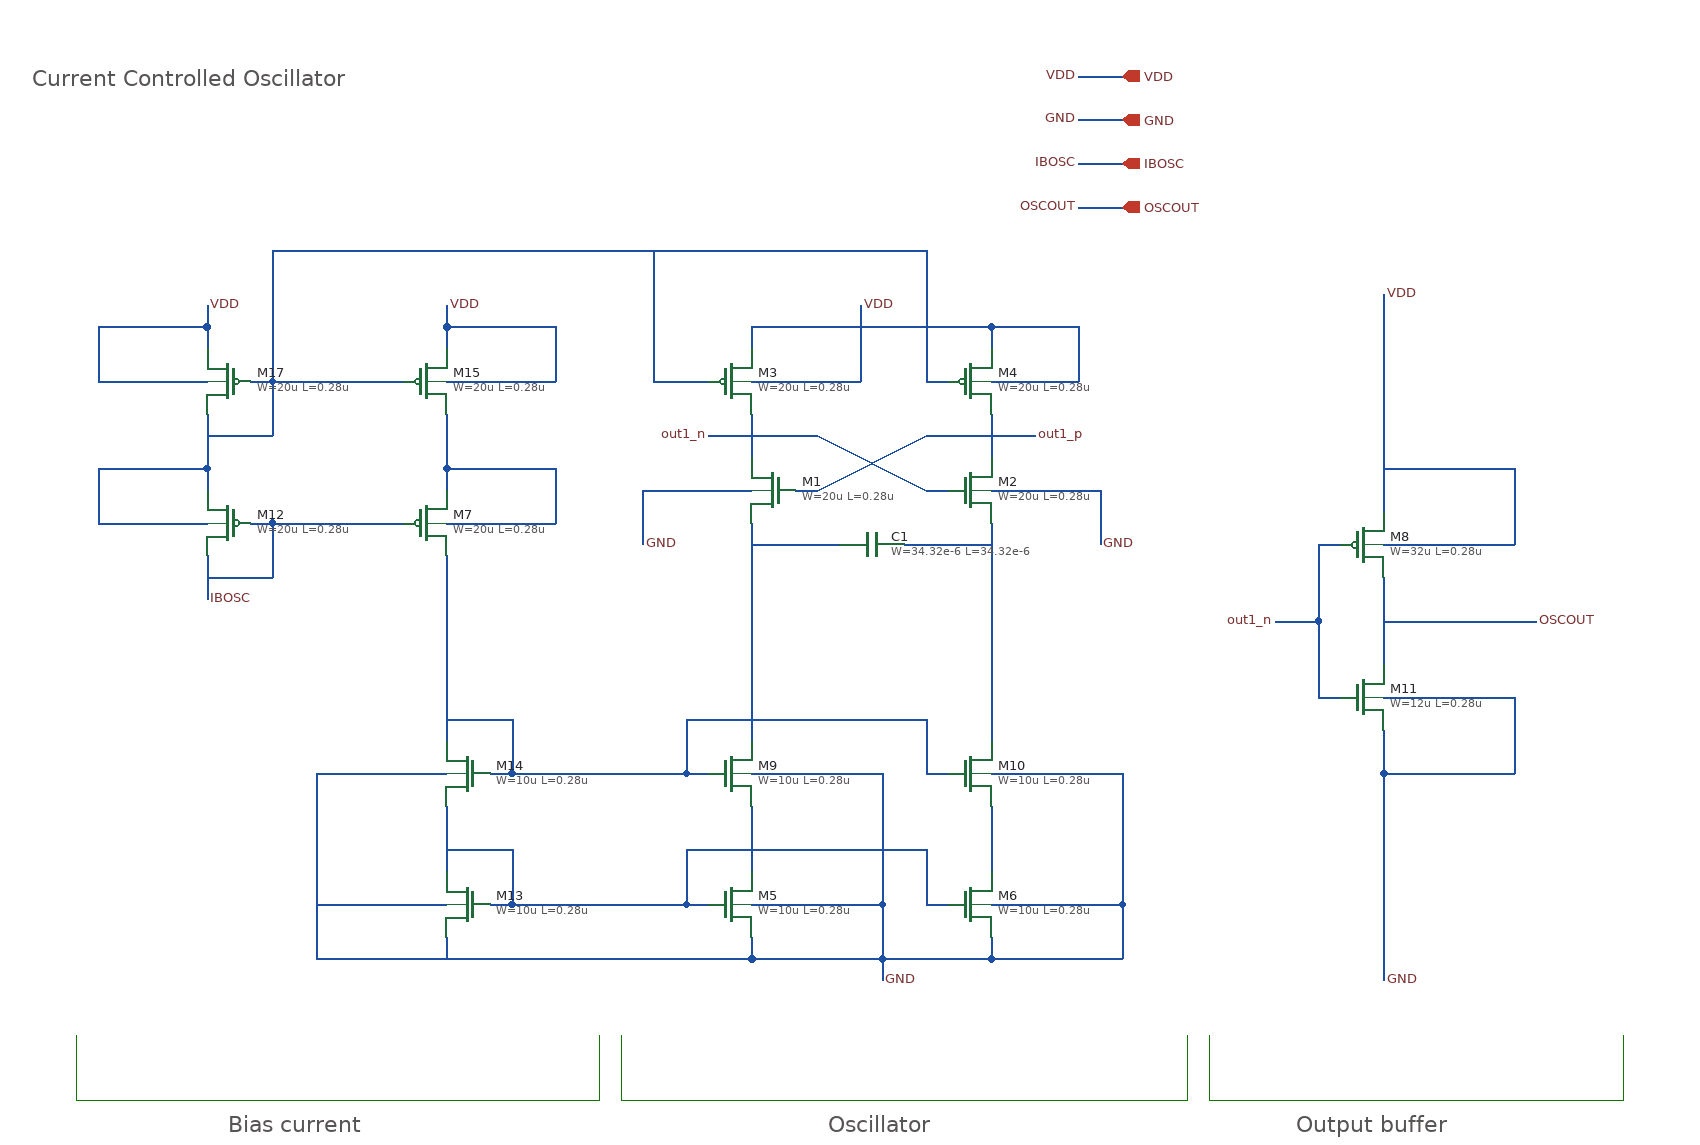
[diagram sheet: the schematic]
v {xschem version=3.4.8RC file_version=1.3}
G {}
K {}
V {}
S {}
F {}
E {}
L 4 80 -200 80 -140 {}
L 4 80 -140 560 -140 {}
L 4 560 -200 560 -140 {}
L 4 580 -200 580 -140 {}
L 4 580 -140 1100 -140 {}
L 4 1100 -200 1100 -140 {}
L 4 1120 -200 1120 -140 {}
L 4 1120 -140 1500 -140 {}
L 4 1500 -200 1500 -140 {}
T {Bias current} 220 -130 0 0 0.6 0.6 {}
T {Oscillator} 770 -130 0 0 0.6 0.6 {}
T {Output buffer} 1200 -130 0 0 0.6 0.6 {}
T {Current Controlled Oscillator} 40 -1090 0 0 1 1 {}
N 820 -270 820 -250 {lab=GND}
N 690 -270 700 -270 {lab=GND}
N 700 -290 700 -270 {lab=GND}
N 920 -290 920 -270 {lab=GND}
N 700 -390 700 -350 {lab=#net1}
N 920 -390 920 -350 {lab=#net2}
N 700 -770 700 -730 {lab=out1_n}
N 920 -770 920 -730 {lab=out1_p}
N 920 -850 920 -830 {lab=VDD}
N 700 -850 920 -850 {lab=VDD}
N 700 -850 700 -830 {lab=VDD}
N 800 -870 800 -850 {lab=VDD}
N 690 -700 700 -700 {lab=GND}
N 920 -800 930 -800 {lab=VDD}
N 920 -700 930 -700 {lab=GND}
N 860 -700 880 -700 {lab=out1_n}
N 740 -700 760 -700 {lab=out1_p}
N 920 -750 960 -750 {lab=out1_p}
N 660 -750 700 -750 {lab=out1_n}
N 920 -320 1040 -320 {lab=GND}
N 700 -320 820 -320 {lab=GND}
N 820 -320 820 -270 {lab=GND}
N 640 -320 660 -320 {lab=#net3}
N 640 -370 640 -320 {lab=#net3}
N 740 -370 860 -370 {lab=#net3}
N 860 -370 860 -320 {lab=#net3}
N 860 -320 880 -320 {lab=#net3}
N 920 -270 1040 -270 {lab=GND}
N 820 -270 920 -270 {lab=GND}
N 700 -270 820 -270 {lab=GND}
N 700 -670 700 -610 {lab=#net4}
N 700 -410 700 -390 {lab=#net1}
N 920 -410 920 -390 {lab=#net2}
N 920 -670 920 -610 {lab=#net5}
N 640 -370 740 -370 {lab=#net3}
N 930 -800 1000 -800 {lab=VDD}
N 1000 -850 1000 -800 {lab=VDD}
N 920 -850 1000 -850 {lab=VDD}
N 600 -700 690 -700 {lab=GND}
N 600 -700 600 -650 {lab=GND}
N 1040 -320 1040 -270 {lab=GND}
N 930 -700 1020 -700 {lab=GND}
N 1020 -700 1020 -650 {lab=GND}
N 700 -750 760 -750 {lab=out1_n}
N 760 -750 860 -700 {lab=out1_n}
N 860 -750 920 -750 {lab=out1_p}
N 760 -700 860 -750 {lab=out1_p}
N 880 -650 920 -650 {lab=#net5}
N 700 -800 800 -800 {lab=VDD}
N 800 -850 800 -800 {lab=VDD}
N 610 -840 610 -800 {lab=#net6}
N 610 -800 660 -800 {lab=#net6}
N 860 -800 880 -800 {lab=#net6}
N 860 -920 860 -800 {lab=#net6}
N 260 -920 860 -920 {lab=#net6}
N 610 -920 610 -840 {lab=#net6}
N 700 -440 820 -440 {lab=GND}
N 640 -440 660 -440 {lab=#net7}
N 640 -490 640 -440 {lab=#net7}
N 740 -490 860 -490 {lab=#net7}
N 860 -490 860 -440 {lab=#net7}
N 860 -440 880 -440 {lab=#net7}
N 640 -490 740 -490 {lab=#net7}
N 820 -440 820 -320 {lab=GND}
N 920 -440 1040 -440 {lab=GND}
N 1040 -440 1040 -320 {lab=GND}
N 700 -610 700 -470 {lab=#net4}
N 920 -610 920 -470 {lab=#net5}
N 700 -650 780 -650 {lab=#net4}
N 420 -370 480 -370 {lab=#net3}
N 420 -490 480 -490 {lab=#net7}
N 480 -490 480 -440 {lab=#net7}
N 420 -410 420 -350 {lab=#net3}
N 480 -370 480 -320 {lab=#net3}
N 460 -440 480 -440 {lab=#net7}
N 460 -320 480 -320 {lab=#net3}
N 420 -290 420 -270 {lab=GND}
N 500 -320 560 -320 {lab=#net3}
N 420 -800 500 -800 {lab=VDD}
N 420 -770 420 -750 {lab=#net8}
N 360 -800 380 -800 {lab=#net6}
N 480 -440 500 -440 {lab=#net7}
N 480 -320 500 -320 {lab=#net3}
N 300 -270 440 -270 {lab=GND}
N 310 -440 420 -440 {lab=GND}
N 300 -440 300 -270 {lab=GND}
N 300 -440 310 -440 {lab=GND}
N 500 -800 520 -800 {lab=VDD}
N 420 -850 520 -850 {lab=VDD}
N 420 -850 420 -830 {lab=VDD}
N 540 -270 690 -270 {lab=GND}
N 240 -800 260 -800 {lab=#net6}
N 260 -800 360 -800 {lab=#net6}
N 200 -850 200 -830 {lab=VDD}
N 100 -800 200 -800 {lab=VDD}
N 100 -850 100 -800 {lab=VDD}
N 200 -860 200 -850 {lab=VDD}
N 200 -870 200 -860 {lab=VDD}
N 100 -850 200 -850 {lab=VDD}
N 200 -770 200 -730 {lab=#net6}
N 200 -750 260 -750 {lab=#net6}
N 260 -800 260 -750 {lab=#net6}
N 300 -320 420 -320 {lab=GND}
N 520 -850 520 -800 {lab=VDD}
N 420 -870 420 -850 {lab=VDD}
N 260 -920 260 -800 {lab=#net6}
N 500 -440 640 -440 {lab=#net7}
N 560 -320 640 -320 {lab=#net3}
N 440 -270 540 -270 {lab=GND}
N 1280 -620 1280 -540 {lab=OSCOUT}
N 1280 -480 1280 -440 {lab=GND}
N 1280 -650 1400 -650 {lab=VDD}
N 1280 -510 1400 -510 {lab=GND}
N 1280 -440 1280 -250 {lab=GND}
N 1280 -440 1400 -440 {lab=GND}
N 1400 -510 1400 -440 {lab=GND}
N 1280 -870 1280 -680 {lab=VDD}
N 1280 -720 1400 -720 {lab=VDD}
N 1400 -720 1400 -650 {lab=VDD}
N 1180 -580 1220 -580 {lab=out1_n}
N 1220 -650 1220 -580 {lab=out1_n}
N 1220 -650 1240 -650 {lab=out1_n}
N 1220 -580 1220 -510 {lab=out1_n}
N 1220 -510 1240 -510 {lab=out1_n}
N 1290 -580 1420 -580 {lab=OSCOUT}
N 1280 -580 1290 -580 {lab=OSCOUT}
N 420 -670 500 -670 {lab=#net8}
N 420 -640 420 -620 {lab=#net7}
N 360 -670 380 -670 {lab=IBOSC}
N 500 -670 520 -670 {lab=#net8}
N 420 -720 520 -720 {lab=#net8}
N 420 -720 420 -700 {lab=#net8}
N 240 -670 260 -670 {lab=IBOSC}
N 260 -670 360 -670 {lab=IBOSC}
N 200 -720 200 -700 {lab=#net6}
N 100 -670 200 -670 {lab=#net6}
N 100 -720 100 -670 {lab=#net6}
N 100 -720 200 -720 {lab=#net6}
N 200 -640 200 -600 {lab=IBOSC}
N 200 -620 260 -620 {lab=IBOSC}
N 260 -670 260 -620 {lab=IBOSC}
N 520 -720 520 -670 {lab=#net8}
N 200 -730 200 -720 {lab=#net6}
N 420 -750 420 -720 {lab=#net8}
N 420 -620 420 -470 {lab=#net7}
N 840 -650 880 -650 {lab=#net5}
N 1280 -880 1280 -870 {lab=VDD}
N 1000 -1080 1040 -1080 {lab=VDD}
N 1000 -1040 1040 -1040 {lab=GND}
N 1000 -1000 1040 -1000 {lab=IBOSC}
N 1000 -960 1040 -960 {lab=OSCOUT}
C {devices/lab_pin.sym} 960 -750 0 1 {name=l4 sig_type=std_logic lab=out1_p}
C {symbols/nfet_03v3.sym} 720 -700 0 1 {name=M1
L=0.28u
W=20u
nf=1
mult=1
ad="'int((nf+1)/2) * W/nf * 0.18u'"
pd="'2*int((nf+1)/2) * (W/nf + 0.18u)'"
as="'int((nf+2)/2) * W/nf * 0.18u'"
ps="'2*int((nf+2)/2) * (W/nf + 0.18u)'"
nrd="'0.18u / W'" nrs="'0.18u / W'"
sa=0 sb=0 sd=0
model=nfet_03v3
spiceprefix=X
}
C {symbols/nfet_03v3.sym} 900 -700 0 0 {name=M2
L=0.28u
W=20u
nf=1
mult=1
ad="'int((nf+1)/2) * W/nf * 0.18u'"
pd="'2*int((nf+1)/2) * (W/nf + 0.18u)'"
as="'int((nf+2)/2) * W/nf * 0.18u'"
ps="'2*int((nf+2)/2) * (W/nf + 0.18u)'"
nrd="'0.18u / W'" nrs="'0.18u / W'"
sa=0 sb=0 sd=0
model=nfet_03v3
spiceprefix=X
}
C {symbols/cap_mim_2f0fF.sym} 810 -650 1 0 {name=C1
W=34.32e-6
L=34.32e-6
model=cap_mim_2f0fF
spiceprefix=X
m=1}
C {symbols/nfet_03v3.sym} 680 -320 0 0 {name=M5
L=0.28u
W=10u
nf=1
mult=1
ad="'int((nf+1)/2) * W/nf * 0.18u'"
pd="'2*int((nf+1)/2) * (W/nf + 0.18u)'"
as="'int((nf+2)/2) * W/nf * 0.18u'"
ps="'2*int((nf+2)/2) * (W/nf + 0.18u)'"
nrd="'0.18u / W'" nrs="'0.18u / W'"
sa=0 sb=0 sd=0
model=nfet_03v3
spiceprefix=X
}
C {symbols/nfet_03v3.sym} 900 -320 0 0 {name=M6
L=0.28u
W=10u
nf=1
mult=1
ad="'int((nf+1)/2) * W/nf * 0.18u'"
pd="'2*int((nf+1)/2) * (W/nf + 0.18u)'"
as="'int((nf+2)/2) * W/nf * 0.18u'"
ps="'2*int((nf+2)/2) * (W/nf + 0.18u)'"
nrd="'0.18u / W'" nrs="'0.18u / W'"
sa=0 sb=0 sd=0
model=nfet_03v3
spiceprefix=X
}
C {devices/lab_pin.sym} 660 -750 0 0 {name=l8 sig_type=std_logic lab=out1_n}
C {symbols/pfet_03v3.sym} 900 -800 0 0 {name=M4
L=0.28u
W=20u
nf=1
mult=1
ad="'int((nf+1)/2) * W/nf * 0.18u'"
pd="'2*int((nf+1)/2) * (W/nf + 0.18u)'"
as="'int((nf+2)/2) * W/nf * 0.18u'"
ps="'2*int((nf+2)/2) * (W/nf + 0.18u)'"
nrd="'0.18u / W'" nrs="'0.18u / W'"
sa=0 sb=0 sd=0
model=pfet_03v3
spiceprefix=X
}
C {symbols/pfet_03v3.sym} 680 -800 0 0 {name=M3
L=0.28u
W=20u
nf=1
mult=1
ad="'int((nf+1)/2) * W/nf * 0.18u'"
pd="'2*int((nf+1)/2) * (W/nf + 0.18u)'"
as="'int((nf+2)/2) * W/nf * 0.18u'"
ps="'2*int((nf+2)/2) * (W/nf + 0.18u)'"
nrd="'0.18u / W'" nrs="'0.18u / W'"
sa=0 sb=0 sd=0
model=pfet_03v3
spiceprefix=X
}
C {symbols/nfet_03v3.sym} 680 -440 0 0 {name=M9
L=0.28u
W=10u
nf=1
mult=1
ad="'int((nf+1)/2) * W/nf * 0.18u'"
pd="'2*int((nf+1)/2) * (W/nf + 0.18u)'"
as="'int((nf+2)/2) * W/nf * 0.18u'"
ps="'2*int((nf+2)/2) * (W/nf + 0.18u)'"
nrd="'0.18u / W'" nrs="'0.18u / W'"
sa=0 sb=0 sd=0
model=nfet_03v3
spiceprefix=X
}
C {symbols/nfet_03v3.sym} 900 -440 0 0 {name=M10
L=0.28u
W=10u
nf=1
mult=1
ad="'int((nf+1)/2) * W/nf * 0.18u'"
pd="'2*int((nf+1)/2) * (W/nf + 0.18u)'"
as="'int((nf+2)/2) * W/nf * 0.18u'"
ps="'2*int((nf+2)/2) * (W/nf + 0.18u)'"
nrd="'0.18u / W'" nrs="'0.18u / W'"
sa=0 sb=0 sd=0
model=nfet_03v3
spiceprefix=X
}
C {symbols/nfet_03v3.sym} 440 -320 0 1 {name=M13
L=0.28u
W=10u
nf=1
mult=1
ad="'int((nf+1)/2) * W/nf * 0.18u'"
pd="'2*int((nf+1)/2) * (W/nf + 0.18u)'"
as="'int((nf+2)/2) * W/nf * 0.18u'"
ps="'2*int((nf+2)/2) * (W/nf + 0.18u)'"
nrd="'0.18u / W'" nrs="'0.18u / W'"
sa=0 sb=0 sd=0
model=nfet_03v3
spiceprefix=X
}
C {symbols/nfet_03v3.sym} 440 -440 0 1 {name=M14
L=0.28u
W=10u
nf=1
mult=1
ad="'int((nf+1)/2) * W/nf * 0.18u'"
pd="'2*int((nf+1)/2) * (W/nf + 0.18u)'"
as="'int((nf+2)/2) * W/nf * 0.18u'"
ps="'2*int((nf+2)/2) * (W/nf + 0.18u)'"
nrd="'0.18u / W'" nrs="'0.18u / W'"
sa=0 sb=0 sd=0
model=nfet_03v3
spiceprefix=X
}
C {symbols/pfet_03v3.sym} 400 -800 0 0 {name=M15
L=0.28u
W=20u
nf=1
mult=1
ad="'int((nf+1)/2) * W/nf * 0.18u'"
pd="'2*int((nf+1)/2) * (W/nf + 0.18u)'"
as="'int((nf+2)/2) * W/nf * 0.18u'"
ps="'2*int((nf+2)/2) * (W/nf + 0.18u)'"
nrd="'0.18u / W'" nrs="'0.18u / W'"
sa=0 sb=0 sd=0
model=pfet_03v3
spiceprefix=X
}
C {symbols/pfet_03v3.sym} 220 -800 0 1 {name=M17
L=0.28u
W=20u
nf=1
mult=1
ad="'int((nf+1)/2) * W/nf * 0.18u'"
pd="'2*int((nf+1)/2) * (W/nf + 0.18u)'"
as="'int((nf+2)/2) * W/nf * 0.18u'"
ps="'2*int((nf+2)/2) * (W/nf + 0.18u)'"
nrd="'0.18u / W'" nrs="'0.18u / W'"
sa=0 sb=0 sd=0
model=pfet_03v3
spiceprefix=X
}
C {symbols/pfet_03v3.sym} 1260 -650 0 0 {name=M8
L=0.28u
W=32u
nf=1
mult=1
ad="'int((nf+1)/2) * W/nf * 0.18u'"
pd="'2*int((nf+1)/2) * (W/nf + 0.18u)'"
as="'int((nf+2)/2) * W/nf * 0.18u'"
ps="'2*int((nf+2)/2) * (W/nf + 0.18u)'"
nrd="'0.18u / W'" nrs="'0.18u / W'"
sa=0 sb=0 sd=0
model=pfet_03v3
spiceprefix=X
}
C {symbols/nfet_03v3.sym} 1260 -510 0 0 {name=M11
L=0.28u
W=12u
nf=1
mult=1
ad="'int((nf+1)/2) * W/nf * 0.18u'"
pd="'2*int((nf+1)/2) * (W/nf + 0.18u)'"
as="'int((nf+2)/2) * W/nf * 0.18u'"
ps="'2*int((nf+2)/2) * (W/nf + 0.18u)'"
nrd="'0.18u / W'" nrs="'0.18u / W'"
sa=0 sb=0 sd=0
model=nfet_03v3
spiceprefix=X
}
C {devices/lab_pin.sym} 1180 -580 0 0 {name=l17 sig_type=std_logic lab=out1_n}
C {devices/lab_pin.sym} 1420 -580 0 1 {name=l18 sig_type=std_logic lab=OSCOUT}
C {symbols/pfet_03v3.sym} 400 -670 0 0 {name=M7
L=0.28u
W=20u
nf=1
mult=1
ad="'int((nf+1)/2) * W/nf * 0.18u'"
pd="'2*int((nf+1)/2) * (W/nf + 0.18u)'"
as="'int((nf+2)/2) * W/nf * 0.18u'"
ps="'2*int((nf+2)/2) * (W/nf + 0.18u)'"
nrd="'0.18u / W'" nrs="'0.18u / W'"
sa=0 sb=0 sd=0
model=pfet_03v3
spiceprefix=X
}
C {symbols/pfet_03v3.sym} 220 -670 0 1 {name=M12
L=0.28u
W=20u
nf=1
mult=1
ad="'int((nf+1)/2) * W/nf * 0.18u'"
pd="'2*int((nf+1)/2) * (W/nf + 0.18u)'"
as="'int((nf+2)/2) * W/nf * 0.18u'"
ps="'2*int((nf+2)/2) * (W/nf + 0.18u)'"
nrd="'0.18u / W'" nrs="'0.18u / W'"
sa=0 sb=0 sd=0
model=pfet_03v3
spiceprefix=X
}
C {devices/lab_pin.sym} 200 -870 0 1 {name=l19 sig_type=std_logic lab=VDD}
C {devices/lab_pin.sym} 420 -870 0 1 {name=l20 sig_type=std_logic lab=VDD}
C {devices/lab_pin.sym} 800 -870 0 1 {name=l21 sig_type=std_logic lab=VDD}
C {devices/lab_pin.sym} 1280 -880 0 1 {name=l1 sig_type=std_logic lab=VDD}
C {devices/lab_pin.sym} 200 -600 0 1 {name=l7 sig_type=std_logic lab=IBOSC}
C {devices/lab_pin.sym} 820 -250 0 1 {name=l6 sig_type=std_logic lab=GND}
C {devices/lab_pin.sym} 1280 -250 0 1 {name=l9 sig_type=std_logic lab=GND}
C {devices/lab_pin.sym} 1000 -1080 0 0 {name=l10 sig_type=std_logic lab=VDD}
C {ipin.sym} 1040 -1080 0 1 {name=p1 lab=VDD}
C {devices/lab_pin.sym} 1000 -1040 0 0 {name=l14 sig_type=std_logic lab=GND}
C {ipin.sym} 1040 -1040 0 1 {name=p2 lab=GND}
C {devices/lab_pin.sym} 1000 -1000 0 0 {name=l22 sig_type=std_logic lab=IBOSC}
C {ipin.sym} 1040 -1000 0 1 {name=p3 lab=IBOSC}
C {devices/lab_pin.sym} 1000 -960 0 0 {name=l23 sig_type=std_logic lab=OSCOUT}
C {opin.sym} 1040 -960 0 0 {name=p4 lab=OSCOUT}
C {devices/lab_pin.sym} 600 -650 0 1 {name=l15 sig_type=std_logic lab=GND}
C {devices/lab_pin.sym} 1020 -650 0 1 {name=l16 sig_type=std_logic lab=GND}
